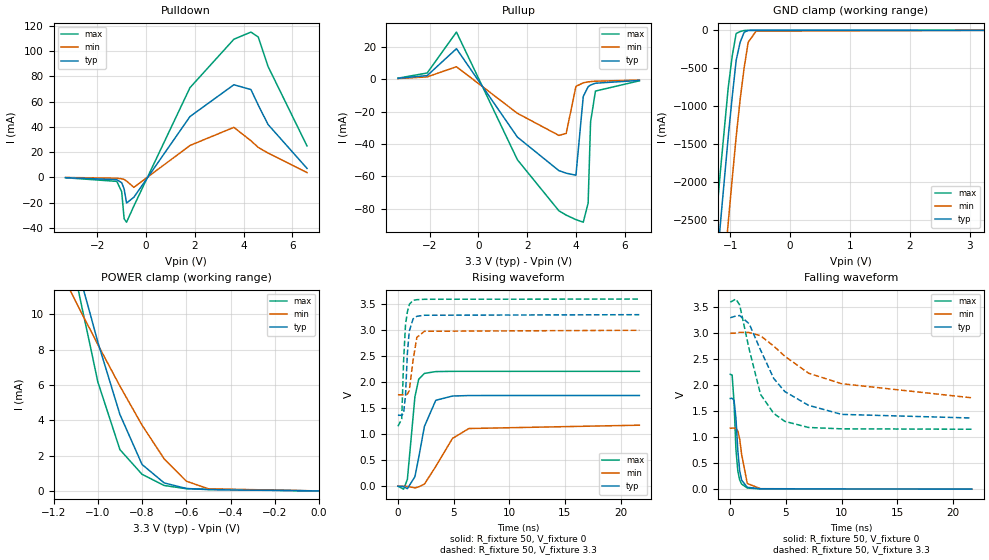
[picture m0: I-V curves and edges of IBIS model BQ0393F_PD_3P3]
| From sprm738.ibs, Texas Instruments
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|BQ0393F_PZ_3P3; PULLDOWN_OFF
|   Model Cell BQ0393F_PD_3P3
|BQ0393F_PD_3P3
[Model]   BQ0393F_PD_3P3
Model_type   I/O
Polarity   Non-Inverting
Enable   Active-Low
Vinl =  1.15
Vinh =  1.65
Cref =  15.0001pF
Rref =  101.0000M
Vref =  0V
Vmeas =  1.65
C_comp   1.2p   1.2p   1.2p
[Model Spec]
Vinl   1.15   1.05   1.15
Vinh   1.65   1.65   1.65
[Temperature Range]   25   125   -40
[Voltage Range]   3.3   3   3.6
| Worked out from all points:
|   slope of the pulldown table from 0 to 0.495 V, typ, clamps not added: 32.6 ohm
|   slope of the pullup table from 0 to 0.495 V, typ, clamps not added: 41.1 ohm
|   GND clamp passes 1 mA (typ) near -0.66 V on its own axis
|   POWER clamp passes 1 mA (typ) near -0.75 V on its own axis
|   rising waveform, R_fixture 50, V_fixture 0: 20-80 % time 985ps typ, 1.96ns min, 559ps max; typ from 0.003 V to 1.75 V
|   rising waveform, R_fixture 50, V_fixture 3.3: 20-80 % time 310ps typ, 405ps min, 292ps max; typ from 1.37 V to 3.3 V
|   falling waveform, R_fixture 50, V_fixture 0: 20-80 % time 354ps typ, 471ps min, 334ps max; typ from 1.75 V to 0.003 V
|   falling waveform, R_fixture 50, V_fixture 3.3: 20-80 % time 3.43ns typ, 6.59ns min, 1.87ns max; typ from 3.3 V to 1.37 V
[POWER_clamp]
|   voltage   I(typ)   I(min)   I(max)
-3.3V     126.2mA    68.25mA    170.7mA
-1.133V   14.63mA    11.56mA    14.28mA
-1.1V     13.03mA    10.73mA    12.09mA
-1.067V   11.5mA     9.919mA    10.12mA
-1.033V   9.965mA    9.106mA    8.149mA
-1V       8.433mA    8.293mA    6.18mA
-900mV    4.329mA    5.935mA    2.338mA
-800mV    1.498mA    3.724mA    940.4uA
-700mV    453.1uA    1.815mA    307.7uA
-600mV    140.5uA    551.8uA    126.7uA
-500mV    71.72uA    118.7uA    92.77uA
0V        342.4pA    2.022nA    393.4pA
[Pulldown]
|   voltage   I(typ)   I(min)   I(max)
-3.3V     -235.3uA   -110.8uA   -321uA
-1.2V     -1.831mA   -650uA     -3.19mA
-1V       -4.234mA   -1.115mA   -11.41mA
-900mV    -9.125mA   -1.665mA   -32.86mA
-800mV    -20.38mA   -2.93mA    -35.56mA
-500mV    -15.78mA   -7.942mA   -22.73mA
1.8V      48.21mA    25.28mA    71.1mA
3.6V      73.43mA    39.64mA    109.5mA
4.3V      69.63mA    29.03mA    115.2mA
4.6V      57.33mA    23.76mA    111.3mA
5V        41.97mA    19.31mA    88.04mA
6.6V      7.109mA    3.772mA    24.87mA
[Pullup]
|   voltage   I(typ)   I(min)   I(max)
-3.3V     707uA      560.2uA    814uA
-2.1V     2.419mA    1.616mA    4.016mA
-900mV    19.05mA    7.888mA    29.32mA
1.6V      -35.65mA   -20.92mA   -49.67mA
3.3V      -56.37mA   -34.59mA   -81.2mA
3.6V      -57.96mA   -33.36mA   -83.9mA
4V        -59.21mA   -4.264mA   -86.68mA
4.3V      -10.46mA   -2.036mA   -88.27mA
4.5V      -4.473mA   -1.491mA   -76.45mA
4.6V      -3.426mA   -1.312mA   -26.26mA
4.8V      -2.312mA   -1.056mA   -7.154mA
6.6V      -565.6uA   -375.3uA   -812.8uA
[GND_clamp]
|   voltage   I(typ)   I(min)   I(max)
-3.3V     -23.34A    -24.42A    -22.71A
-1.3V     -3.808A    -4.968A    -3.114A
-1.233V   -3.19A     -4.349A    -2.495A
-1.167V   -2.579A    -3.735A    -1.888A
-1.033V   -1.408A    -2.537A    -758.5mA
-966.7mV  -880.9mA   -1.962A    -341.5mA
-900mV    -395.3mA   -1.403A    -41.68mA
-833.3mV  -155.9mA   -909mA     -15.84mA
-766.7mV  -24.6mA    -494.1mA   -2.104mA
-700mV    -1.48mA    -158.3mA   -472.8uA
-566.7mV  -177.4uA   -9.924mA   -230.7uA
3.233V    -8.123uA   19.85uA    -59.92uA
[Ramp]
| variable   typ   min   max
dV/dt_f   1.585347/5.840648n   1.017997/10.83799n   2.006226/3.203276n
dV/dt_r   1.433532/1.563798n   0.9651326/3.106073n   1.812012/0.875588n
R_load = 50
[Rising Waveform]
R_fixture = 50
V_fixture = 0
V_fixture_min = 0
V_fixture_max = 0
|   time   V(typ)   V(min)   V(max)
0s        2.676mV    2.336mV    3.398mV
508ps     -2.985mV   2.614mV    -53.67mV
848ps     -44.05mV   122.7uV    133.9mV
1.528ns   186.6mV    -28.78mV   1.724V
1.868ns   555.2mV    -8.932mV   2.059V
2.38ns    1.153V     43.08mV    2.171V
3.4ns     1.655V     383.3mV    2.206V
4.9ns     1.736V     921.6mV    2.211V
6.376ns   1.746V     1.112V     2.211V
21.69ns   1.747V     1.176V     2.211V
[Rising Waveform]
R_fixture = 50
V_fixture = 3.3
V_fixture_min = 3
V_fixture_max = 3.6
|   time   V(typ)   V(min)   V(max)
0s        1.368V     1.76V      1.155V
340ps     1.365V     1.76V      1.294V
508ps     1.407V     1.757V     2.402V
680ps     1.746V     1.757V     3.103V
848ps     2.557V     1.773V     3.352V
1.02ns    2.983V     1.842V     3.496V
1.36ns    3.218V     2.422V     3.577V
1.7ns     3.269V     2.864V     3.588V
2.38ns    3.289V     2.981V     3.596V
21.69ns   3.3V       3V         3.6V
[Falling Waveform]
R_fixture = 50
V_fixture = 0
V_fixture_min = 0
V_fixture_max = 0
|   time   V(typ)   V(min)   V(max)
0s        1.747V     1.176V     2.211V
168ps     1.751V     1.176V     2.198V
340ps     1.709V     1.178V     1.669V
508ps     1.373V     1.17V      766.6mV
680ps     744.1mV    1.123V     351.2mV
848ps     353.3mV    965.4mV    178mV
1.02ns    176.6mV    674.4mV    100.8mV
1.528ns   38.4mV     112.1mV    25.47mV
2.72ns    9.785mV    11.44mV    6.896mV
21.69ns   2.716mV    2.442mV    3.316mV
[Falling Waveform]
R_fixture = 50
V_fixture = 3.3
V_fixture_min = 3
V_fixture_max = 3.6
|   time   V(typ)   V(min)   V(max)
0s        3.3V       3V         3.599V
508ps     3.333V     3.005V     3.659V
848ps     3.342V     3.02V      3.543V
1.7ns     3.184V     3.015V     2.693V
2.72ns    2.679V     2.954V     1.825V
3.908ns   2.131V     2.754V     1.459V
4.9ns     1.88V      2.56V      1.307V
7.032ns   1.615V     2.233V     1.189V
10ns      1.441V     2.031V     1.163V
21.69ns   1.371V     1.76V      1.155V
